VERSION 5.8 ;
BUSBITCHARS "[]" ;
DIVIDERCHAR "/" ;
UNITS
    DATABASE MICRONS 1000 ;
END UNITS

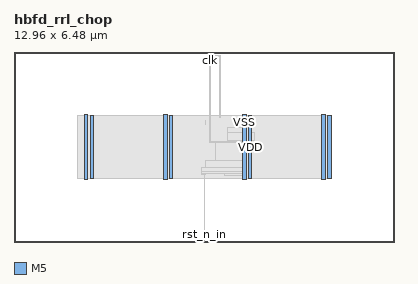
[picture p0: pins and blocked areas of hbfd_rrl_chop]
MACRO hbfd_rrl_chop
  FOREIGN hbfd_rrl_chop 0 0 ;
  CLASS BLOCK ;
  SIZE 12.96 BY 6.48 ;
  PIN clk
    DIRECTION INPUT ;
    USE SIGNAL ;
    PORT
      LAYER M5 ;
        RECT  6.672 6.396 6.696 6.48 ;
    END
  END clk
  PIN rst_n
    DIRECTION OUTPUT ;
    USE SIGNAL ;
    PORT
      LAYER M5 ;
        RECT  6.768 6.396 6.792 6.48 ;
    END
  END rst_n
  PIN rst_n_in
    DIRECTION INPUT ;
    USE SIGNAL ;
    PORT
      LAYER M5 ;
        RECT  6.48 0 6.504 0.084 ;
    END
  END rst_n_in
  PIN VDD
    DIRECTION INOUT ;
    USE POWER ;
    PORT
      LAYER M5 ;
        RECT  10.692 2.151 10.812 4.329 ;
        RECT  7.992 2.151 8.112 4.329 ;
        RECT  5.292 2.151 5.412 4.329 ;
        RECT  2.592 2.151 2.712 4.329 ;
    END
  END VDD
  PIN VSS
    DIRECTION INOUT ;
    USE GROUND ;
    PORT
      LAYER M5 ;
        RECT  10.5 2.137 10.62 4.343 ;
        RECT  7.8 2.137 7.92 4.343 ;
        RECT  5.1 2.137 5.22 4.343 ;
        RECT  2.4 2.137 2.52 4.343 ;
    END
  END VSS
  OBS
    LAYER RVTN ;
     RECT  2.16 2.16 10.8 2.295 ;
     RECT  2.16 2.565 10.8 2.835 ;
     RECT  2.16 3.105 10.8 3.375 ;
     RECT  2.16 3.645 10.8 3.915 ;
     RECT  2.16 4.185 10.8 4.32 ;
    LAYER RVTP ;
     RECT  2.16 2.295 10.8 2.565 ;
     RECT  2.16 2.835 10.8 3.105 ;
     RECT  2.16 3.375 10.8 3.645 ;
     RECT  2.16 3.915 10.8 4.185 ;
    LAYER M1 ;
     RECT  2.16 2.151 10.8 4.329 ;
    LAYER M2 ;
     RECT  2.16 2.151 10.8 4.329 ;
     RECT  10.8 2.421 10.812 4.059 ;
    LAYER M3 ;
     RECT  7.815 2.143 7.905 2.263 ;
     RECT  6.408 2.299 6.426 2.335 ;
     RECT  7.164 2.263 7.905 2.335 ;
     RECT  2.415 2.143 2.505 2.413 ;
     RECT  5.115 2.143 5.205 2.413 ;
     RECT  6.408 2.335 7.905 2.413 ;
     RECT  10.515 2.143 10.605 2.413 ;
     RECT  6.408 2.413 8.097 2.525 ;
     RECT  6.516 2.525 8.097 2.795 ;
     RECT  6.876 2.795 8.097 3.437 ;
     RECT  7.272 3.437 8.097 3.451 ;
     RECT  7.272 3.451 8.19 3.749 ;
     RECT  7.272 3.749 8.097 3.911 ;
     RECT  2.415 2.413 2.697 4.067 ;
     RECT  5.115 2.413 5.397 4.067 ;
     RECT  7.815 3.911 8.097 4.067 ;
     RECT  10.515 2.413 10.797 4.067 ;
     RECT  6.516 3.991 6.534 4.145 ;
     RECT  2.415 4.067 2.505 4.337 ;
     RECT  5.115 4.067 5.205 4.337 ;
     RECT  7.815 4.067 7.905 4.337 ;
     RECT  10.515 4.067 10.605 4.337 ;
     RECT  7.02 4.261 7.038 6.365 ;
    LAYER M4 ;
     RECT  2.408 2.148 2.512 4.332 ;
     RECT  2.512 2.418 2.704 4.062 ;
     RECT  5.108 2.148 5.212 4.332 ;
     RECT  5.212 2.418 5.404 4.062 ;
     RECT  6.397 2.304 6.515 2.328 ;
     RECT  6.757 6.336 7.049 6.36 ;
     RECT  6.661 3.408 7.808 3.432 ;
     RECT  7.808 2.148 7.912 4.332 ;
     RECT  7.912 2.418 8.104 4.062 ;
     RECT  10.508 2.148 10.612 4.332 ;
     RECT  10.612 2.418 10.804 4.062 ;
    LAYER M5 ;
     RECT  2.4 2.137 2.52 2.151 ;
     RECT  5.1 2.137 5.22 2.151 ;
     RECT  7.8 2.137 7.92 2.151 ;
     RECT  10.5 2.137 10.62 2.151 ;
     RECT  6.48 0.016 6.504 2.339 ;
     RECT  2.4 2.151 2.712 4.329 ;
     RECT  5.1 2.151 5.412 4.329 ;
     RECT  7.8 2.151 8.112 4.329 ;
     RECT  10.5 2.151 10.812 4.329 ;
     RECT  2.4 4.329 2.52 4.343 ;
     RECT  5.1 4.329 5.22 4.343 ;
     RECT  7.8 4.329 7.92 4.343 ;
     RECT  10.5 4.329 10.62 4.343 ;
     RECT  6.672 3.397 6.696 6.325 ;
     RECT  6.672 6.325 6.792 6.416 ;
  END
END hbfd_rrl_chop
END LIBRARY
